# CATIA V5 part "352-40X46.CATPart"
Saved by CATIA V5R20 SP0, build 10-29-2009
Part number: 352-40X46
Definition: NONE
Nomenclature: 352-40X46
Source: Unknown
Description: 352-40X46
Bounding box of the stored display mesh (mm): x 0 to 46, y -24 to 24, z -24 to 24
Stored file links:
  C:\Users\Utente\Desktop\IO LAVORO\3D X SITO CF\X SITO\PLASTICA\352\352-40X46.CATPart

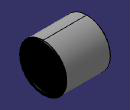
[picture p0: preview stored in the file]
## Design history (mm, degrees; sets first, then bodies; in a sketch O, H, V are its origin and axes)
Body1 "352-40X46" (main body)
  Solid1: solid without history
